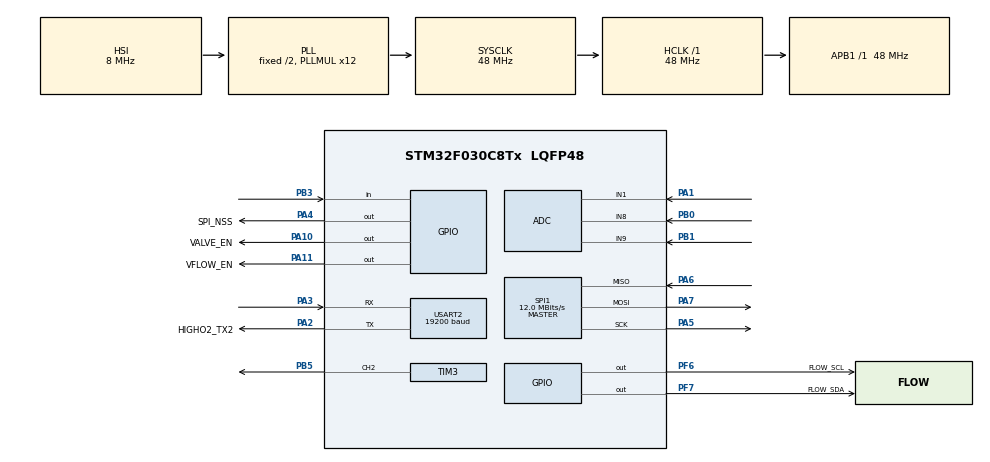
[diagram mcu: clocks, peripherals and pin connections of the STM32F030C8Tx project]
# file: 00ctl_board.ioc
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ADC.ContinuousConvMode=ENABLE
ADC.DMAContinuousRequests=ENABLE
ADC.Overrun=ADC_OVR_DATA_OVERWRITTEN
ADC.SamplingTime=ADC_SAMPLETIME_239CYCLES_5
Dma.ADC.2.Direction=DMA_PERIPH_TO_MEMORY
Dma.ADC.2.Instance=DMA1_Channel1
Dma.ADC.2.MemDataAlignment=DMA_MDATAALIGN_HALFWORD
Dma.ADC.2.MemInc=DMA_MINC_ENABLE
Dma.ADC.2.Mode=DMA_CIRCULAR
Dma.ADC.2.PeriphDataAlignment=DMA_PDATAALIGN_HALFWORD
Dma.ADC.2.PeriphInc=DMA_PINC_DISABLE
Dma.ADC.2.Priority=DMA_PRIORITY_HIGH
Dma.Request0=USART2_RX
Dma.Request1=USART2_TX
Dma.Request2=ADC
Dma.USART2_RX.0.Direction=DMA_PERIPH_TO_MEMORY
Dma.USART2_RX.0.Instance=DMA1_Channel5
Dma.USART2_RX.0.MemDataAlignment=DMA_MDATAALIGN_BYTE
Dma.USART2_RX.0.MemInc=DMA_MINC_ENABLE
Dma.USART2_RX.0.Mode=DMA_CIRCULAR
Dma.USART2_RX.0.PeriphDataAlignment=DMA_PDATAALIGN_BYTE
Dma.USART2_RX.0.PeriphInc=DMA_PINC_DISABLE
Dma.USART2_RX.0.Priority=DMA_PRIORITY_LOW
Dma.USART2_TX.1.Direction=DMA_MEMORY_TO_PERIPH
Dma.USART2_TX.1.Instance=DMA1_Channel4
Dma.USART2_TX.1.MemDataAlignment=DMA_MDATAALIGN_BYTE
Dma.USART2_TX.1.MemInc=DMA_MINC_ENABLE
Dma.USART2_TX.1.Mode=DMA_NORMAL
Dma.USART2_TX.1.PeriphDataAlignment=DMA_PDATAALIGN_BYTE
Dma.USART2_TX.1.PeriphInc=DMA_PINC_DISABLE
Dma.USART2_TX.1.Priority=DMA_PRIORITY_LOW
FREERTOS.Tasks01=defaultTask,0,256,StartDefaultTask,Default,NULL,Dynamic,NULL,NULL
FREERTOS.configTOTAL_HEAP_SIZE=4096
Mcu.Family=STM32F0
Mcu.Name=STM32F030C8Tx
Mcu.Package=LQFP48
NVIC.ADC1_IRQn=true\:3\:0\:false\:false\:true\:true\:true\:true
NVIC.DMA1_Channel1_IRQn=true\:3\:0\:true\:false\:true\:true\:false\:true
NVIC.DMA1_Channel4_5_IRQn=true\:3\:0\:false\:false\:true\:true\:false\:true
NVIC.USART2_IRQn=true\:3\:0\:false\:false\:true\:true\:true\:true
PA1.Signal=SharedAnalog_PA1
PA10.GPIO_Label=VALVE_EN
PA10.GPIO_ModeDefaultOutputPP=GPIO_MODE_OUTPUT_PP
PA10.GPIO_PuPd=GPIO_NOPULL
PA10.GPIO_Speed=GPIO_SPEED_FREQ_LOW
PA10.PinState=GPIO_PIN_SET
PA10.Signal=GPIO_Output
PA11.GPIO_Label=VFLOW_EN
PA11.GPIO_ModeDefaultOutputPP=GPIO_MODE_OUTPUT_PP
PA11.GPIO_PuPd=GPIO_NOPULL
PA11.GPIO_Speed=GPIO_SPEED_FREQ_LOW
PA11.PinState=GPIO_PIN_SET
PA11.Signal=GPIO_Output
PA13.Mode=Serial_Wire
PA13.Signal=SYS_SWDIO
PA14.Mode=Serial_Wire
PA14.Signal=SYS_SWCLK
PA2.GPIO_Label=HIGHO2_TX2
PA2.GPIO_ModeDefaultPP=GPIO_MODE_AF_PP
PA2.GPIO_PuPd=GPIO_PULLUP
PA2.GPIO_Speed=GPIO_SPEED_FREQ_HIGH
PA2.Mode=Asynchronous
PA2.Signal=USART2_TX
PA3.GPIO_ModeDefaultPP=GPIO_MODE_AF_PP
PA3.GPIO_PuPd=GPIO_PULLUP
PA3.GPIO_Speed=GPIO_SPEED_FREQ_HIGH
PA3.Mode=Asynchronous
PA3.Signal=USART2_RX
PA4.GPIO_Label=SPI_NSS
PA4.GPIO_ModeDefaultOutputPP=GPIO_MODE_OUTPUT_PP
PA4.GPIO_PuPd=GPIO_NOPULL
PA4.GPIO_Speed=GPIO_SPEED_FREQ_LOW
PA4.PinState=GPIO_PIN_SET
PA4.Signal=GPIO_Output
PA5.GPIO_Mode=GPIO_MODE_AF_PP
PA5.GPIO_PuPd=GPIO_NOPULL
PA5.GPIO_Speed=GPIO_SPEED_FREQ_HIGH
PA5.Mode=Full_Duplex_Master
PA5.Signal=SPI1_SCK
PA6.GPIO_Mode=GPIO_MODE_AF_PP
PA6.GPIO_PuPd=GPIO_NOPULL
PA6.GPIO_Speed=GPIO_SPEED_FREQ_HIGH
PA6.Mode=Full_Duplex_Master
PA6.Signal=SPI1_MISO
PA7.GPIO_Mode=GPIO_MODE_AF_PP
PA7.GPIO_PuPd=GPIO_NOPULL
PA7.GPIO_Speed=GPIO_SPEED_FREQ_HIGH
PA7.Mode=Full_Duplex_Master
PA7.Signal=SPI1_MOSI
PB0.Signal=SharedAnalog_PB0
PB1.Signal=SharedAnalog_PB1
PB3.GPIO_Mode=GPIO_MODE_INPUT
PB3.GPIO_PuPd=GPIO_NOPULL
PB3.Signal=GPIO_Input
PB5.GPIO_ModeDefaultPP=GPIO_MODE_AF_PP
PB5.GPIO_PuPd=GPIO_NOPULL
PB5.GPIO_Speed=GPIO_SPEED_FREQ_LOW
PB5.Signal=S_TIM3_CH2
PF0-OSC_IN.Mode=HSE-External-Oscillator
PF0-OSC_IN.Signal=RCC_OSC_IN
PF1-OSC_OUT.Mode=HSE-External-Oscillator
PF1-OSC_OUT.Signal=RCC_OSC_OUT
PF6.GPIO_Label=FLOW_SCL
PF6.GPIO_ModeDefaultOutputPP=GPIO_MODE_OUTPUT_OD
PF6.GPIO_PuPd=GPIO_NOPULL
PF6.GPIO_Speed=GPIO_SPEED_FREQ_LOW
PF6.PinState=GPIO_PIN_SET
PF6.Signal=GPIO_Output
PF7.GPIO_Label=FLOW_SDA
PF7.GPIO_ModeDefaultOutputPP=GPIO_MODE_OUTPUT_OD
PF7.GPIO_PuPd=GPIO_NOPULL
PF7.GPIO_Speed=GPIO_SPEED_FREQ_LOW
PF7.PinState=GPIO_PIN_SET
PF7.Signal=GPIO_Output
ProjectManager.HeapSize=0x260
ProjectManager.StackSize=0x500
ProjectManager.TargetToolchain=MDK-ARM V5
RCC.AHBFreq_Value=48000000
RCC.APB1Freq_Value=48000000
RCC.APB1TimFreq_Value=48000000
RCC.HCLKFreq_Value=48000000
RCC.PLLMUL=RCC_PLL_MUL12
RCC.SYSCLKFreq_VALUE=48000000
RCC.SYSCLKSource=RCC_SYSCLKSOURCE_PLLCLK
SH.S_TIM3_CH2.0=TIM3_CH2,PWM Generation2 CH2
SH.SharedAnalog_PA1.0=GPIO_Analog
SH.SharedAnalog_PA1.1=ADC_IN1,IN1
SH.SharedAnalog_PB0.0=GPIO_Analog
SH.SharedAnalog_PB0.1=ADC_IN8,IN8
SH.SharedAnalog_PB1.0=GPIO_Analog
SH.SharedAnalog_PB1.1=ADC_IN9,IN9
SPI1.BaudRatePrescaler=SPI_BAUDRATEPRESCALER_4
SPI1.CalculateBaudRate=12.0 MBits/s
SPI1.DataSize=SPI_DATASIZE_8BIT
SPI1.Direction=SPI_DIRECTION_2LINES
SPI1.Mode=SPI_MODE_MASTER
SPI1.NSSPMode=SPI_NSS_PULSE_ENABLE
SPI1.VirtualType=VM_MASTER
TIM3.AutoReloadPreload=TIM_AUTORELOAD_PRELOAD_ENABLE
TIM3.Channel-PWM\ Generation2\ CH2=TIM_CHANNEL_2
TIM3.OCPolarity_2=TIM_OCPOLARITY_LOW
TIM3.Period=2400-1
TIM3.Prescaler=20-1
TIM3.Pulse-PWM\ Generation2\ CH2=400
USART2.BaudRate=19200
USART2.VirtualMode-Asynchronous=VM_ASYNC
VP_FREERTOS_VS_CMSIS_V1.Mode=CMSIS_V1
board=custom

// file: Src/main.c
/* USER CODE BEGIN Header */
/**
  ******************************************************************************
  * @file           : main.c
  * @brief          : Main program body
  ******************************************************************************
  * This notice applies to any and all portions of this file
  * that are not between comment pairs USER CODE BEGIN and
  * USER CODE END. Other portions of this file, whether
  * inserted by the user or by software development tools
  * are owned by their respective copyright owners.
  *
  * Copyright (c) 2019 STMicroelectronics International N.V.
  * All rights reserved.
  *
  * Redistribution and use in source and binary forms, with or without
  * modification, are permitted, provided that the following conditions are met:
  *
  * 1. Redistribution of source code must retain the above copyright notice,
  *    this list of conditions and the following disclaimer.
  * 2. Redistributions in binary form must reproduce the above copyright notice,
  *    this list of conditions and the following disclaimer in the documentation
  *    and/or other materials provided with the distribution.
  * 3. Neither the name of STMicroelectronics nor the names of other
  *    contributors to this software may be used to endorse or promote products
  *    derived from this software without specific written permission.
  * 4. This software, including modifications and/or derivative works of this
  *    software, must execute solely and exclusively on microcontroller or
  *    microprocessor devices manufactured by or for STMicroelectronics.
  * 5. Redistribution and use of this software other than as permitted under
  *    this license is void and will automatically terminate your rights under
  *    this license.
  *
  * THIS SOFTWARE IS PROVIDED BY STMICROELECTRONICS AND CONTRIBUTORS "AS IS"
  * AND ANY EXPRESS, IMPLIED OR STATUTORY WARRANTIES, INCLUDING, BUT NOT
  * LIMITED TO, THE IMPLIED WARRANTIES OF MERCHANTABILITY, FITNESS FOR A
  * PARTICULAR PURPOSE AND NON-INFRINGEMENT OF THIRD PARTY INTELLECTUAL PROPERTY
  * RIGHTS ARE DISCLAIMED TO THE FULLEST EXTENT PERMITTED BY LAW. IN NO EVENT
  * SHALL STMICROELECTRONICS OR CONTRIBUTORS BE LIABLE FOR ANY DIRECT, INDIRECT,
  * INCIDENTAL, SPECIAL, EXEMPLARY, OR CONSEQUENTIAL DAMAGES (INCLUDING, BUT NOT
  * LIMITED TO, PROCUREMENT OF SUBSTITUTE GOODS OR SERVICES; LOSS OF USE, DATA,
  * OR PROFITS; OR BUSINESS INTERRUPTION) HOWEVER CAUSED AND ON ANY THEORY OF
  * LIABILITY, WHETHER IN CONTRACT, STRICT LIABILITY, OR TORT (INCLUDING
  * NEGLIGENCE OR OTHERWISE) ARISING IN ANY WAY OUT OF THE USE OF THIS SOFTWARE,
  * EVEN IF ADVISED OF THE POSSIBILITY OF SUCH DAMAGE.
  *
  ******************************************************************************
  */
/* USER CODE END Header */

#include "main.h"
#include "cmsis_os.h"

/* USER CODE BEGIN Includes */
#include "interface_module.h"
/* USER CODE END Includes */

/* USER CODE BEGIN PM */
uint16_t ADC_Value[4]={0};
/* USER CODE END PM */

ADC_HandleTypeDef hadc;
DMA_HandleTypeDef hdma_adc;

SPI_HandleTypeDef hspi1;

TIM_HandleTypeDef htim3;

UART_HandleTypeDef huart2;
DMA_HandleTypeDef hdma_usart2_rx;
DMA_HandleTypeDef hdma_usart2_tx;

osThreadId defaultTaskHandle;
extern uint32_t band_rate;

void SystemClock_Config(void);
static void MX_GPIO_Init(void);
static void MX_DMA_Init(void);
static void MX_SPI1_Init(void);
void MX_USART2_UART_Init(void);
static void MX_ADC_Init(void);
static void MX_TIM3_Init(void);
void StartDefaultTask(void const * argument);

  #if 1
	#define APPLICATION_ADDRESS     (uint32_t)0x08003000
#if   (defined ( __CC_ARM ))
__IO uint32_t VectorTable[48] __attribute__((at(0x20000000)));
#elif (defined (__ICCARM__))
#pragma location = 0x20000000
__no_init __IO uint32_t VectorTable[48];
#elif defined   (  __GNUC__  )
__IO uint32_t VectorTable[48] __attribute__((section(".RAMVectorTable")));
#endif
#endif
int main(void)
{
	uint32_t i;

  /* MCU Configuration--------------------------------------------------------*/

  /* Reset of all peripherals, Initializes the Flash interface and the Systick. */
  //uint32_t i = 0;
  HAL_Init();

  /* Configure the system clock */
  SystemClock_Config();
  #if 1
   for(i = 0; i < 48; i++)
  {
			VectorTable[i] = *(__IO uint32_t*)(APPLICATION_ADDRESS + (i<<2));
  }
   /* Enable the SYSCFG peripheral clock*/
  __HAL_RCC_SYSCFG_CLK_ENABLE();
  /* Remap SRAM at 0x00000000 */
  __HAL_SYSCFG_REMAPMEMORY_SRAM();
  #endif

  /* Initialize all configured peripherals */
  MX_GPIO_Init();
  MX_DMA_Init();
  MX_SPI1_Init();
  MX_USART2_UART_Init();
  MX_ADC_Init();
  MX_TIM3_Init();
  /* USER CODE BEGIN 2 */
	HAL_ADC_Start_DMA(&hadc, (uint32_t*)&ADC_Value, 4);
	interface_module_init_sys();
  /* USER CODE END 2 */

  /* Create the thread(s) */
  /* definition and creation of defaultTask */
  osThreadDef(defaultTask, StartDefaultTask, osPriorityNormal, 0, 256);
  defaultTaskHandle = osThreadCreate(osThread(defaultTask), NULL);

  /* USER CODE BEGIN RTOS_THREADS */
  interface_module_create_task();

  /* USER CODE END RTOS_THREADS */

  /* Start scheduler */
  osKernelStart();

  /* We should never get here as control is now taken by the scheduler */

  /* Infinite loop */
  while (1)
  {

  }
}

void SystemClock_Config(void)
{
  RCC_OscInitTypeDef RCC_OscInitStruct = {0};
  RCC_ClkInitTypeDef RCC_ClkInitStruct = {0};

  /** Initializes the CPU, AHB and APB busses clocks
  */
  RCC_OscInitStruct.OscillatorType = RCC_OSCILLATORTYPE_HSI|RCC_OSCILLATORTYPE_HSI14;
  RCC_OscInitStruct.HSIState = RCC_HSI_ON;
  RCC_OscInitStruct.HSI14State = RCC_HSI14_ON;
  RCC_OscInitStruct.HSICalibrationValue = RCC_HSICALIBRATION_DEFAULT;
  RCC_OscInitStruct.HSI14CalibrationValue = 16;
  RCC_OscInitStruct.PLL.PLLState = RCC_PLL_ON;
  RCC_OscInitStruct.PLL.PLLSource = RCC_PLLSOURCE_HSI;
  RCC_OscInitStruct.PLL.PLLMUL = RCC_PLL_MUL12;
  RCC_OscInitStruct.PLL.PREDIV = RCC_PREDIV_DIV1;
  if (HAL_RCC_OscConfig(&RCC_OscInitStruct) != HAL_OK)
  {
    Error_Handler();
  }
  /** Initializes the CPU, AHB and APB busses clocks
  */
  RCC_ClkInitStruct.ClockType = RCC_CLOCKTYPE_HCLK|RCC_CLOCKTYPE_SYSCLK
                              |RCC_CLOCKTYPE_PCLK1;
  RCC_ClkInitStruct.SYSCLKSource = RCC_SYSCLKSOURCE_PLLCLK;
  RCC_ClkInitStruct.AHBCLKDivider = RCC_SYSCLK_DIV1;
  RCC_ClkInitStruct.APB1CLKDivider = RCC_HCLK_DIV1;

  if (HAL_RCC_ClockConfig(&RCC_ClkInitStruct, FLASH_LATENCY_1) != HAL_OK)
  {
    Error_Handler();
  }
}

static void MX_ADC_Init(void)
{

  ADC_ChannelConfTypeDef sConfig = {0};

  /** Configure the global features of the ADC (Clock, Resolution, Data Alignment and number of conversion)
  */
  hadc.Instance = ADC1;
  hadc.Init.ClockPrescaler = ADC_CLOCK_ASYNC_DIV1;
  hadc.Init.Resolution = ADC_RESOLUTION_12B;
  hadc.Init.DataAlign = ADC_DATAALIGN_RIGHT;
  hadc.Init.ScanConvMode = ADC_SCAN_DIRECTION_FORWARD;
  hadc.Init.EOCSelection = ADC_EOC_SINGLE_CONV;
  hadc.Init.LowPowerAutoWait = DISABLE;
  hadc.Init.LowPowerAutoPowerOff = DISABLE;
  hadc.Init.ContinuousConvMode = ENABLE;
  hadc.Init.DiscontinuousConvMode = DISABLE;
  hadc.Init.ExternalTrigConv = ADC_SOFTWARE_START;
  hadc.Init.ExternalTrigConvEdge = ADC_EXTERNALTRIGCONVEDGE_NONE;
  hadc.Init.DMAContinuousRequests = ENABLE;
  hadc.Init.Overrun = ADC_OVR_DATA_OVERWRITTEN;
  if (HAL_ADC_Init(&hadc) != HAL_OK)
  {
    Error_Handler();
  }
  /** Configure for the selected ADC regular channel to be converted.
  */
  sConfig.Channel = ADC_CHANNEL_1;
  sConfig.Rank = ADC_RANK_CHANNEL_NUMBER;
  sConfig.SamplingTime = ADC_SAMPLETIME_239CYCLES_5;
  if (HAL_ADC_ConfigChannel(&hadc, &sConfig) != HAL_OK)
  {
    Error_Handler();
  }
  /** Configure for the selected ADC regular channel to be converted.
  */
  sConfig.Channel = ADC_CHANNEL_8;
  if (HAL_ADC_ConfigChannel(&hadc, &sConfig) != HAL_OK)
  {
    Error_Handler();
  }
  /** Configure for the selected ADC regular channel to be converted.
  */
  sConfig.Channel = ADC_CHANNEL_9;
  if (HAL_ADC_ConfigChannel(&hadc, &sConfig) != HAL_OK)
  {
    Error_Handler();
  }
  sConfig.Channel = ADC_CHANNEL_0;
  if (HAL_ADC_ConfigChannel(&hadc, &sConfig) != HAL_OK)
  {
    Error_Handler();
  }
  /* USER CODE BEGIN ADC_Init 2 */
//	HAL_ADC_Start(&hadc);
//	__HAL_DMA_ENABLE(&hdma_adc);
  /* USER CODE END ADC_Init 2 */

}

static void MX_SPI1_Init(void)
{

  /* SPI1 parameter configuration*/
  hspi1.Instance = SPI1;
  hspi1.Init.Mode = SPI_MODE_MASTER;
  hspi1.Init.Direction = SPI_DIRECTION_2LINES;
  hspi1.Init.DataSize = SPI_DATASIZE_8BIT;
  hspi1.Init.CLKPolarity = SPI_POLARITY_LOW;
  hspi1.Init.CLKPhase = SPI_PHASE_1EDGE;
  hspi1.Init.NSS = SPI_NSS_SOFT;
  hspi1.Init.BaudRatePrescaler = SPI_BAUDRATEPRESCALER_4;
  hspi1.Init.FirstBit = SPI_FIRSTBIT_MSB;
  hspi1.Init.TIMode = SPI_TIMODE_DISABLE;
  hspi1.Init.CRCCalculation = SPI_CRCCALCULATION_DISABLE;
  hspi1.Init.CRCPolynomial = 7;
  hspi1.Init.CRCLength = SPI_CRC_LENGTH_DATASIZE;
  hspi1.Init.NSSPMode = SPI_NSS_PULSE_ENABLE;
  if (HAL_SPI_Init(&hspi1) != HAL_OK)
  {
    Error_Handler();
  }

}

static void MX_TIM3_Init(void)
{

  TIM_MasterConfigTypeDef sMasterConfig = {0};
  TIM_OC_InitTypeDef sConfigOC = {0};

  htim3.Instance = TIM3;
  htim3.Init.Prescaler = 20-1;
  htim3.Init.CounterMode = TIM_COUNTERMODE_UP;
  htim3.Init.Period = 2400-1;
  htim3.Init.ClockDivision = TIM_CLOCKDIVISION_DIV1;
  htim3.Init.AutoReloadPreload = TIM_AUTORELOAD_PRELOAD_ENABLE;
  if (HAL_TIM_PWM_Init(&htim3) != HAL_OK)
  {
    Error_Handler();
  }
  sMasterConfig.MasterOutputTrigger = TIM_TRGO_RESET;
  sMasterConfig.MasterSlaveMode = TIM_MASTERSLAVEMODE_DISABLE;
  if (HAL_TIMEx_MasterConfigSynchronization(&htim3, &sMasterConfig) != HAL_OK)
  {
    Error_Handler();
  }
  sConfigOC.OCMode = TIM_OCMODE_PWM1;
  sConfigOC.Pulse = 400;
  sConfigOC.OCPolarity = TIM_OCPOLARITY_LOW;
  sConfigOC.OCFastMode = TIM_OCFAST_DISABLE;
  if (HAL_TIM_PWM_ConfigChannel(&htim3, &sConfigOC, TIM_CHANNEL_2) != HAL_OK)
  {
    Error_Handler();
  }
  HAL_TIM_MspPostInit(&htim3);

}

void MX_USART2_UART_Init(void)
{

  huart2.Instance = USART2;
  huart2.Init.BaudRate = band_rate;
  huart2.Init.WordLength = UART_WORDLENGTH_8B;
  huart2.Init.StopBits = UART_STOPBITS_1;
  huart2.Init.Parity = UART_PARITY_NONE;
  huart2.Init.Mode = UART_MODE_TX_RX;
  huart2.Init.HwFlowCtl = UART_HWCONTROL_NONE;
  huart2.Init.OverSampling = UART_OVERSAMPLING_16;
  huart2.Init.OneBitSampling = UART_ONE_BIT_SAMPLE_DISABLE;
  huart2.AdvancedInit.AdvFeatureInit = UART_ADVFEATURE_NO_INIT;
  if (HAL_UART_Init(&huart2) != HAL_OK)
  {
    Error_Handler();
  }
  /* USER CODE BEGIN USART2_Init 2 */
//	huart2.Instance = USART2;
//  huart2.Init.BaudRate = 115200;
//  huart2.Init.WordLength = UART_WORDLENGTH_8B;
//  huart2.Init.StopBits = UART_STOPBITS_1;
//  huart2.Init.Parity = UART_PARITY_NONE;
//  huart2.Init.Mode = UART_MODE_TX_RX;
//  huart2.Init.HwFlowCtl = UART_HWCONTROL_NONE;
//  huart2.Init.OverSampling = UART_OVERSAMPLING_16;
//  huart2.Init.OneBitSampling = UART_ONE_BIT_SAMPLE_DISABLE;
//  huart2.AdvancedInit.AdvFeatureInit = UART_ADVFEATURE_NO_INIT;
//  if (HAL_UART_Init(&huart2) != HAL_OK)
//  {
//    Error_Handler();
//  }
  /* USER CODE END USART2_Init 2 */

}

static void MX_DMA_Init(void)
{

  /* DMA controller clock enable */
  __HAL_RCC_DMA1_CLK_ENABLE();

  /* DMA interrupt init */
  /* DMA1_Channel1_IRQn interrupt configuration */
  HAL_NVIC_SetPriority(DMA1_Channel1_IRQn, 3, 0);
  HAL_NVIC_EnableIRQ(DMA1_Channel1_IRQn);
  /* DMA1_Channel4_5_IRQn interrupt configuration */
  HAL_NVIC_SetPriority(DMA1_Channel4_5_IRQn, 3, 0);
  HAL_NVIC_EnableIRQ(DMA1_Channel4_5_IRQn);

}

static void MX_GPIO_Init(void)
{
  GPIO_InitTypeDef GPIO_InitStruct = {0};

  /* GPIO Ports Clock Enable */
  __HAL_RCC_GPIOF_CLK_ENABLE();
  __HAL_RCC_GPIOA_CLK_ENABLE();
  __HAL_RCC_GPIOB_CLK_ENABLE();

  /*Configure GPIO pin Output Level */
  HAL_GPIO_WritePin(GPIOA, SPI_NSS_Pin|VALVE_EN_Pin|VFLOW_EN_Pin, GPIO_PIN_SET);

  /*Configure GPIO pin Output Level */
  HAL_GPIO_WritePin(GPIOF, FLOW_SCL_Pin|FLOW_SDA_Pin, GPIO_PIN_SET);

  /*Configure GPIO pin : PA1 */
  GPIO_InitStruct.Pin = GPIO_PIN_1;
  GPIO_InitStruct.Mode = GPIO_MODE_ANALOG;
  GPIO_InitStruct.Pull = GPIO_NOPULL;
  HAL_GPIO_Init(GPIOA, &GPIO_InitStruct);

  /*Configure GPIO pins : SPI_NSS_Pin VALVE_EN_Pin VFLOW_EN_Pin */
  GPIO_InitStruct.Pin = SPI_NSS_Pin|VALVE_EN_Pin|VFLOW_EN_Pin;
  GPIO_InitStruct.Mode = GPIO_MODE_OUTPUT_PP;
  GPIO_InitStruct.Pull = GPIO_NOPULL;
  GPIO_InitStruct.Speed = GPIO_SPEED_FREQ_LOW;
  HAL_GPIO_Init(GPIOA, &GPIO_InitStruct);

  /*Configure GPIO pins : PB0 PB1 */
  GPIO_InitStruct.Pin = GPIO_PIN_0|GPIO_PIN_1;
  GPIO_InitStruct.Mode = GPIO_MODE_ANALOG;
  GPIO_InitStruct.Pull = GPIO_NOPULL;
  HAL_GPIO_Init(GPIOB, &GPIO_InitStruct);

  /*Configure GPIO pins : FLOW_SCL_Pin FLOW_SDA_Pin */
  GPIO_InitStruct.Pin = FLOW_SCL_Pin|FLOW_SDA_Pin;
  GPIO_InitStruct.Mode = GPIO_MODE_OUTPUT_OD;
  GPIO_InitStruct.Pull = GPIO_NOPULL;
  GPIO_InitStruct.Speed = GPIO_SPEED_FREQ_LOW;
  HAL_GPIO_Init(GPIOF, &GPIO_InitStruct);

  /*Configure GPIO pin : PB3 */
  GPIO_InitStruct.Pin = GPIO_PIN_3;
  GPIO_InitStruct.Mode = GPIO_MODE_INPUT;
  GPIO_InitStruct.Pull = GPIO_NOPULL;
  HAL_GPIO_Init(GPIOB, &GPIO_InitStruct);

  GPIO_InitStruct.Pin = GPIO_PIN_14;
  GPIO_InitStruct.Mode = GPIO_MODE_INPUT;
  GPIO_InitStruct.Pull = GPIO_PULLUP;
  HAL_GPIO_Init(GPIOB, &GPIO_InitStruct);
  GPIO_InitStruct.Pin = GPIO_PIN_15;
  GPIO_InitStruct.Mode = GPIO_MODE_INPUT;
  GPIO_InitStruct.Pull = GPIO_PULLUP;
  HAL_GPIO_Init(GPIOB, &GPIO_InitStruct);
  GPIO_InitStruct.Pin = GPIO_PIN_8;
  GPIO_InitStruct.Mode = GPIO_MODE_INPUT;
  GPIO_InitStruct.Pull = GPIO_PULLUP;
  HAL_GPIO_Init(GPIOA, &GPIO_InitStruct);

  GPIO_InitStruct.Pin = GPIO_PIN_9;
  GPIO_InitStruct.Mode = GPIO_MODE_OUTPUT_OD;
  GPIO_InitStruct.Pull = GPIO_NOPULL;
  GPIO_InitStruct.Speed = GPIO_SPEED_FREQ_LOW;
  HAL_GPIO_Init(GPIOA, &GPIO_InitStruct);

}

void StartDefaultTask(void const * argument)
{

  /* USER CODE BEGIN 5 */
  /* Infinite loop */
  for(;;)
  {
    osDelay(100);
  }
  /* USER CODE END 5 */
}

void Error_Handler(void)
{
}

/************************ (C) COPYRIGHT STMicroelectronics *****END OF FILE****/
